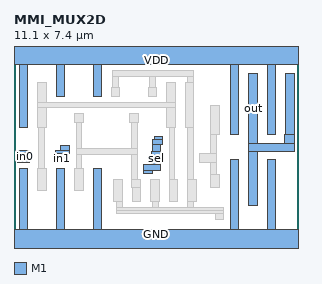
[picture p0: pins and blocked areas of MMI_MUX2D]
MACRO MMI_MUX2D
	CLASS CORE ;
	FOREIGN MMI_MUX2D 0 0 ;
	SIZE 11.1 BY 7.4 ;
	SYMMETRY X Y ;
	SITE CORE1 ;
	PIN out
		DIRECTION output ;
		USE SIGNAL ;
		PORT
			LAYER M1 ;
			RECT 9.14 3.85 9.48 6.55 ;
			LAYER M1 ;
			RECT 10.58 4.175 10.92 6.55 ;
			LAYER M1 ;
			RECT 10.54 3.85 10.92 4.175 ;
			LAYER M1 ;
			RECT 9.14 3.51 10.92 3.85 ;
			LAYER M1 ;
			RECT 9.14 1.44 9.48 3.51 ;
		END
		AntennaDiffArea 3.4977 ;
	END out
	PIN sel
		DIRECTION input ;
		USE SIGNAL ;
		PORT
			LAYER M1 ;
			RECT 5.46 4.01 5.8 4.12 ;
			LAYER M1 ;
			RECT 5.4 3.78 5.8 4.01 ;
			LAYER M1 ;
			RECT 5.4 3.52 5.725 3.78 ;
			LAYER M1 ;
			RECT 5.36 3.005 5.725 3.52 ;
			LAYER M1 ;
			RECT 5.04 2.775 5.725 3.005 ;
			LAYER M1 ;
			RECT 5.04 2.665 5.38 2.775 ;
		END
		AntennaGateArea 1.3284 ;
	END sel
	PIN in1
		DIRECTION input ;
		USE SIGNAL ;
		PORT
			LAYER M1 ;
			RECT 1.83 3.555 2.17 3.775 ;
			LAYER M1 ;
			RECT 1.625 3.435 2.17 3.555 ;
			LAYER M1 ;
			RECT 1.625 3.105 2.075 3.435 ;
		END
		AntennaGateArea 0.9936 ;
	END in1
	PIN GND
		DIRECTION inout ;
		USE GROUND ;
		PORT
			LAYER M1 ;
			RECT 0.2 0.5 0.54 2.845 ;
			LAYER M1 ;
			RECT 1.64 0.5 1.98 2.845 ;
			LAYER M1 ;
			RECT 3.08 0.5 3.42 2.845 ;
			LAYER M1 ;
			RECT 8.42 0.5 8.76 3.2 ;
			LAYER M1 ;
			RECT 9.86 0.5 10.2 3.2 ;
			LAYER M1 ;
			RECT 0 -0.5 11.1 0.5 ;
		END
	END GND
	PIN VDD
		DIRECTION inout ;
		USE POWER ;
		PORT
			LAYER M1 ;
			RECT 0 6.9 11.1 7.9 ;
			LAYER M1 ;
			RECT 0.2 4.45 0.54 6.9 ;
			LAYER M1 ;
			RECT 1.64 5.68 1.98 6.9 ;
			LAYER M1 ;
			RECT 3.08 5.68 3.42 6.9 ;
			LAYER M1 ;
			RECT 8.42 4.175 8.76 6.9 ;
			LAYER M1 ;
			RECT 9.86 4.175 10.2 6.9 ;
		END
	END VDD
	PIN in0
		DIRECTION input ;
		USE SIGNAL ;
		PORT
			LAYER M1 ;
			RECT 0.145 3.5 0.595 3.555 ;
			LAYER M1 ;
			RECT 0.145 3.16 0.65 3.5 ;
			LAYER M1 ;
			RECT 0.145 3.105 0.595 3.16 ;
		END
		AntennaGateArea 0.9936 ;
	END in0
	OBS
		LAYER M1 ;
		RECT 0.92 5.45 1.26 6.21 ;
		LAYER M1 ;
		RECT 3.83 6.44 6.99 6.67 ;
		LAYER M1 ;
		RECT 3.83 6.02 4.06 6.44 ;
		LAYER M1 ;
		RECT 5.27 6.025 5.5 6.44 ;
		LAYER M1 ;
		RECT 6.76 6.21 6.99 6.44 ;
		LAYER M1 ;
		RECT 3.78 5.68 4.12 6.02 ;
		LAYER M1 ;
		RECT 5.22 5.685 5.56 6.025 ;
		LAYER M1 ;
		RECT 5.94 5.45 6.28 6.21 ;
		LAYER M1 ;
		RECT 0.92 5.22 6.28 5.45 ;
		LAYER M1 ;
		RECT 0.92 4.45 1.26 5.22 ;
		LAYER M1 ;
		RECT 2.36 4.65 2.7 4.99 ;
		LAYER M1 ;
		RECT 4.5 4.65 4.84 4.99 ;
		LAYER M1 ;
		RECT 0.97 2.845 1.2 4.45 ;
		LAYER M1 ;
		RECT 2.415 3.635 2.645 4.65 ;
		LAYER M1 ;
		RECT 4.575 3.635 4.805 4.65 ;
		LAYER M1 ;
		RECT 5.94 4.45 6.28 5.22 ;
		LAYER M1 ;
		RECT 6.66 4.45 7 6.21 ;
		LAYER M1 ;
		RECT 2.415 3.405 4.805 3.635 ;
		LAYER M1 ;
		RECT 2.415 2.845 2.645 3.405 ;
		LAYER M1 ;
		RECT 0.92 2.005 1.26 2.845 ;
		LAYER M1 ;
		RECT 2.36 2.005 2.7 2.845 ;
		LAYER M1 ;
		RECT 4.575 2.415 4.805 3.405 ;
		LAYER M1 ;
		RECT 6.04 2.415 6.27 4.45 ;
		LAYER M1 ;
		RECT 6.76 2.415 6.99 4.45 ;
		LAYER M1 ;
		RECT 7.66 4.17 8 5.33 ;
		LAYER M1 ;
		RECT 7.66 3.44 7.89 4.17 ;
		LAYER M1 ;
		RECT 7.225 3.1 7.89 3.44 ;
		LAYER M1 ;
		RECT 7.66 2.645 7.89 3.1 ;
		LAYER M1 ;
		RECT 3.88 1.575 4.22 2.415 ;
		LAYER M1 ;
		RECT 4.575 2.13 4.94 2.415 ;
		LAYER M1 ;
		RECT 4.6 1.575 4.94 2.13 ;
		LAYER M1 ;
		RECT 5.32 1.575 5.66 2.415 ;
		LAYER M1 ;
		RECT 6.04 1.575 6.38 2.415 ;
		LAYER M1 ;
		RECT 6.76 1.575 7.1 2.415 ;
		LAYER M1 ;
		RECT 7.66 2.105 8 2.645 ;
		LAYER M1 ;
		RECT 3.99 1.345 4.22 1.575 ;
		LAYER M1 ;
		RECT 5.38 1.345 5.61 1.575 ;
		LAYER M1 ;
		RECT 6.76 1.345 6.99 1.575 ;
		LAYER M1 ;
		RECT 3.99 1.23 8.17 1.345 ;
		LAYER M1 ;
		RECT 3.99 1.115 8.175 1.23 ;
		LAYER M1 ;
		RECT 7.835 0.89 8.175 1.115 ;
	END
END MMI_MUX2D
